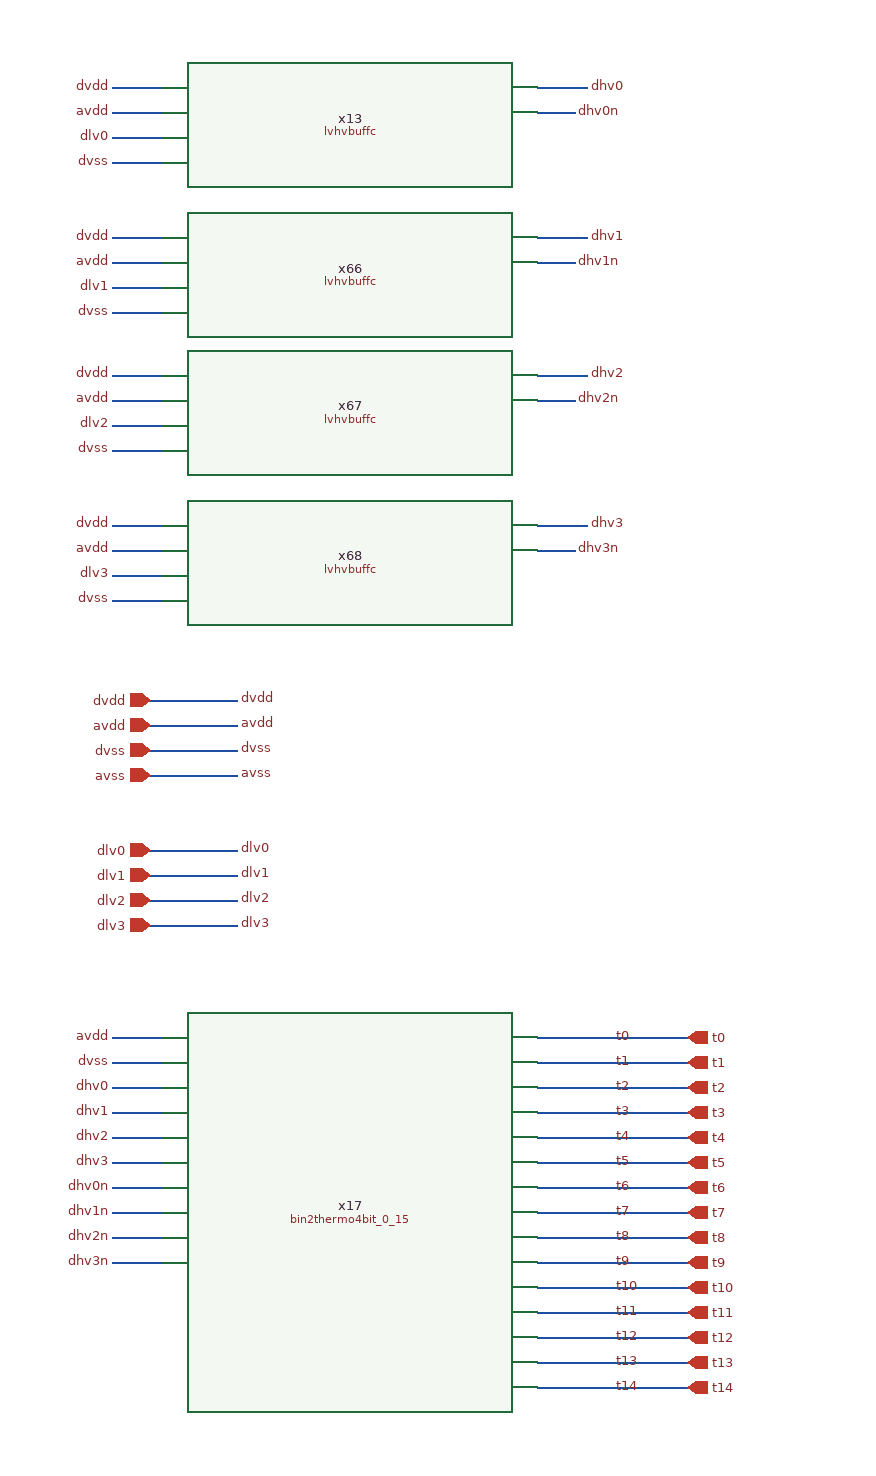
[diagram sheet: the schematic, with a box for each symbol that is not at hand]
v {xschem version=3.4.5 file_version=1.2
}
G {}
K {}
V {}
S {}
E {}
N -930 30 -890 30 {
lab=dvdd}
N -930 50 -890 50 {
lab=avdd}
N -930 70 -890 70 {
lab=dlv0}
N -930 90 -890 90 {
lab=dvss}
N -590 30 -550 30 {
lab=dhv0}
N -930 150 -890 150 {
lab=dvdd}
N -930 170 -890 170 {
lab=avdd}
N -930 190 -890 190 {
lab=dlv1}
N -930 210 -890 210 {
lab=dvss}
N -590 150 -550 150 {
lab=dhv1}
N -930 260 -890 260 {
lab=dvdd}
N -930 280 -890 280 {
lab=avdd}
N -930 300 -890 300 {
lab=dlv2}
N -930 320 -890 320 {
lab=dvss}
N -590 260 -550 260 {
lab=dhv2}
N -930 380 -890 380 {
lab=dvdd}
N -930 400 -890 400 {
lab=avdd}
N -930 420 -890 420 {
lab=dlv3}
N -930 440 -890 440 {
lab=dvss}
N -590 380 -550 380 {
lab=dhv3}
N -590 50 -560 50 {
lab=dhv0n}
N -590 170 -560 170 {
lab=dhv1n}
N -590 280 -560 280 {
lab=dhv2n}
N -590 400 -560 400 {
lab=dhv3n}
N -590 790 -530 790 {
lab=t0}
N -590 810 -530 810 {
lab=t1}
N -590 830 -530 830 {
lab=t2}
N -590 850 -530 850 {
lab=t3}
N -590 870 -530 870 {
lab=t4}
N -590 890 -530 890 {
lab=t5}
N -590 910 -530 910 {
lab=t6}
N -590 930 -530 930 {
lab=t7}
N -590 950 -530 950 {
lab=t8}
N -590 970 -530 970 {
lab=t9}
N -590 990 -530 990 {
lab=t10}
N -590 1010 -530 1010 {
lab=t11}
N -590 1030 -530 1030 {
lab=t12}
N -590 1050 -530 1050 {
lab=t13}
N -590 1070 -530 1070 {
lab=t14}
N -930 790 -890 790 {
lab=avdd}
N -930 810 -890 810 {
lab=dvss}
N -930 830 -890 830 {
lab=dhv0}
N -930 850 -890 850 {
lab=dhv1}
N -930 870 -890 870 {
lab=dhv2}
N -930 890 -890 890 {
lab=dhv3}
N -930 910 -890 910 {
lab=dhv0n}
N -930 930 -890 930 {
lab=dhv1n}
N -930 950 -890 950 {
lab=dhv2n}
N -930 970 -890 970 {
lab=dhv3n}
N -900 520 -830 520 {
lab=dvdd}
N -900 540 -830 540 {
lab=avdd}
N -900 560 -830 560 {
lab=dvss}
N -900 580 -830 580 {
lab=avss}
N -900 640 -830 640 {
lab=dlv0}
N -900 660 -830 660 {
lab=dlv1}
N -900 680 -830 680 {
lab=dlv2}
N -900 700 -830 700 {
lab=dlv3}
N -530 1070 -470 1070 {
lab=t14}
N -530 1050 -470 1050 {
lab=t13}
N -530 1030 -470 1030 {
lab=t12}
N -530 1010 -470 1010 {
lab=t11}
N -530 990 -470 990 {
lab=t10}
N -530 970 -470 970 {
lab=t9}
N -530 950 -470 950 {
lab=t8}
N -530 930 -470 930 {
lab=t7}
N -530 910 -470 910 {
lab=t6}
N -530 890 -470 890 {
lab=t5}
N -530 870 -470 870 {
lab=t4}
N -530 850 -470 850 {
lab=t3}
N -530 830 -470 830 {
lab=t2}
N -530 810 -470 810 {
lab=t1}
N -530 790 -470 790 {
lab=t0}
C {devices/lab_pin.sym} -930 30 0 0 {name=p121 sig_type=std_logic lab=dvdd}
C {devices/lab_pin.sym} -930 50 0 0 {name=p122 sig_type=std_logic lab=avdd}
C {devices/lab_pin.sym} -930 70 0 0 {name=p123 sig_type=std_logic lab=dlv0}
C {devices/lab_pin.sym} -930 90 0 0 {name=p124 sig_type=std_logic lab=dvss}
C {devices/lab_pin.sym} -550 30 0 1 {name=p125 sig_type=std_logic lab=dhv0}
C {devices/lab_pin.sym} -930 150 0 0 {name=p126 sig_type=std_logic lab=dvdd}
C {devices/lab_pin.sym} -930 170 0 0 {name=p127 sig_type=std_logic lab=avdd}
C {devices/lab_pin.sym} -930 190 0 0 {name=p128 sig_type=std_logic lab=dlv1}
C {devices/lab_pin.sym} -930 210 0 0 {name=p129 sig_type=std_logic lab=dvss}
C {devices/lab_pin.sym} -550 150 0 1 {name=p130 sig_type=std_logic lab=dhv1}
C {devices/lab_pin.sym} -930 260 0 0 {name=p651 sig_type=std_logic lab=dvdd}
C {devices/lab_pin.sym} -930 280 0 0 {name=p652 sig_type=std_logic lab=avdd}
C {devices/lab_pin.sym} -930 300 0 0 {name=p653 sig_type=std_logic lab=dlv2}
C {devices/lab_pin.sym} -930 320 0 0 {name=p654 sig_type=std_logic lab=dvss}
C {devices/lab_pin.sym} -550 260 0 1 {name=p655 sig_type=std_logic lab=dhv2}
C {devices/lab_pin.sym} -930 380 0 0 {name=p656 sig_type=std_logic lab=dvdd}
C {devices/lab_pin.sym} -930 400 0 0 {name=p657 sig_type=std_logic lab=avdd}
C {devices/lab_pin.sym} -930 420 0 0 {name=p658 sig_type=std_logic lab=dlv3}
C {devices/lab_pin.sym} -930 440 0 0 {name=p659 sig_type=std_logic lab=dvss}
C {devices/lab_pin.sym} -550 380 0 1 {name=p660 sig_type=std_logic lab=dhv3}
C {lvhvbuffc.sym} -740 60 0 0 {name=x13}
C {lvhvbuffc.sym} -740 180 0 0 {name=x66}
C {lvhvbuffc.sym} -740 290 0 0 {name=x67}
C {lvhvbuffc.sym} -740 410 0 0 {name=x68}
C {devices/lab_pin.sym} -560 50 0 1 {name=p671 sig_type=std_logic lab=dhv0n}
C {devices/lab_pin.sym} -560 170 0 1 {name=p672 sig_type=std_logic lab=dhv1n}
C {devices/lab_pin.sym} -560 280 0 1 {name=p673 sig_type=std_logic lab=dhv2n}
C {devices/lab_pin.sym} -560 400 0 1 {name=p674 sig_type=std_logic lab=dhv3n}
C {bin2thermo4bit_0_15.sym} -740 930 0 0 {name=x17}
C {devices/lab_pin.sym} -530 790 0 1 {name=p161 sig_type=std_logic lab=t0}
C {devices/lab_pin.sym} -530 810 0 1 {name=p162 sig_type=std_logic lab=t1}
C {devices/lab_pin.sym} -530 830 0 1 {name=p163 sig_type=std_logic lab=t2}
C {devices/lab_pin.sym} -530 850 0 1 {name=p164 sig_type=std_logic lab=t3}
C {devices/lab_pin.sym} -530 870 0 1 {name=p165 sig_type=std_logic lab=t4}
C {devices/lab_pin.sym} -530 890 0 1 {name=p166 sig_type=std_logic lab=t5}
C {devices/lab_pin.sym} -530 910 0 1 {name=p167 sig_type=std_logic lab=t6}
C {devices/lab_pin.sym} -530 930 0 1 {name=p168 sig_type=std_logic lab=t7}
C {devices/lab_pin.sym} -530 950 0 1 {name=p169 sig_type=std_logic lab=t8}
C {devices/lab_pin.sym} -530 970 0 1 {name=p170 sig_type=std_logic lab=t9}
C {devices/lab_pin.sym} -530 990 0 1 {name=p171 sig_type=std_logic lab=t10}
C {devices/lab_pin.sym} -530 1010 0 1 {name=p172 sig_type=std_logic lab=t11}
C {devices/lab_pin.sym} -530 1030 0 1 {name=p173 sig_type=std_logic lab=t12}
C {devices/lab_pin.sym} -530 1050 0 1 {name=p174 sig_type=std_logic lab=t13}
C {devices/lab_pin.sym} -530 1070 0 1 {name=p175 sig_type=std_logic lab=t14}
C {devices/lab_pin.sym} -930 790 0 0 {name=p177 sig_type=std_logic lab=avdd}
C {devices/lab_pin.sym} -930 810 0 0 {name=p178 sig_type=std_logic lab=dvss}
C {devices/lab_pin.sym} -930 830 0 0 {name=p179 sig_type=std_logic lab=dhv0}
C {devices/lab_pin.sym} -930 850 0 0 {name=p180 sig_type=std_logic lab=dhv1}
C {devices/lab_pin.sym} -930 870 0 0 {name=p181 sig_type=std_logic lab=dhv2}
C {devices/lab_pin.sym} -930 890 0 0 {name=p182 sig_type=std_logic lab=dhv3}
C {devices/lab_pin.sym} -930 910 0 0 {name=p183 sig_type=std_logic lab=dhv0n}
C {devices/lab_pin.sym} -930 930 0 0 {name=p184 sig_type=std_logic lab=dhv1n}
C {devices/lab_pin.sym} -930 950 0 0 {name=p185 sig_type=std_logic lab=dhv2n}
C {devices/lab_pin.sym} -930 970 0 0 {name=p186 sig_type=std_logic lab=dhv3n}
C {devices/ipin.sym} -900 520 0 0 {name=p187 lab=dvdd}
C {devices/ipin.sym} -900 540 0 0 {name=p188 lab=avdd}
C {devices/ipin.sym} -900 560 0 0 {name=p189 lab=dvss}
C {devices/ipin.sym} -900 580 0 0 {name=p190 lab=avss}
C {devices/lab_pin.sym} -830 520 0 1 {name=p191 sig_type=std_logic lab=dvdd}
C {devices/lab_pin.sym} -830 540 0 1 {name=p192 sig_type=std_logic lab=avdd}
C {devices/lab_pin.sym} -830 560 0 1 {name=p193 sig_type=std_logic lab=dvss}
C {devices/lab_pin.sym} -830 580 0 1 {name=p194 sig_type=std_logic lab=avss}
C {devices/ipin.sym} -900 640 0 0 {name=p195 lab=dlv0}
C {devices/ipin.sym} -900 660 0 0 {name=p196 lab=dlv1}
C {devices/ipin.sym} -900 680 0 0 {name=p197 lab=dlv2}
C {devices/ipin.sym} -900 700 0 0 {name=p198 lab=dlv3}
C {devices/lab_pin.sym} -830 700 0 1 {name=p199 sig_type=std_logic lab=dlv3}
C {devices/lab_pin.sym} -830 680 0 1 {name=p200 sig_type=std_logic lab=dlv2}
C {devices/lab_pin.sym} -830 660 0 1 {name=p201 sig_type=std_logic lab=dlv1}
C {devices/lab_pin.sym} -830 640 0 1 {name=p202 sig_type=std_logic lab=dlv0}
C {devices/opin.sym} -470 790 0 0 {name=p1 lab=t0}
C {devices/opin.sym} -470 810 0 0 {name=p2 lab=t1}
C {devices/opin.sym} -470 830 0 0 {name=p3 lab=t2}
C {devices/opin.sym} -470 850 0 0 {name=p4 lab=t3}
C {devices/opin.sym} -470 870 0 0 {name=p5 lab=t4}
C {devices/opin.sym} -470 890 0 0 {name=p6 lab=t5}
C {devices/opin.sym} -470 910 0 0 {name=p7 lab=t6}
C {devices/opin.sym} -470 930 0 0 {name=p8 lab=t7}
C {devices/opin.sym} -470 950 0 0 {name=p9 lab=t8}
C {devices/opin.sym} -470 970 0 0 {name=p10 lab=t9}
C {devices/opin.sym} -470 990 0 0 {name=p11 lab=t10}
C {devices/opin.sym} -470 1010 0 0 {name=p12 lab=t11}
C {devices/opin.sym} -470 1030 0 0 {name=p13 lab=t12}
C {devices/opin.sym} -470 1050 0 0 {name=p14 lab=t13}
C {devices/opin.sym} -470 1070 0 0 {name=p15 lab=t14}
